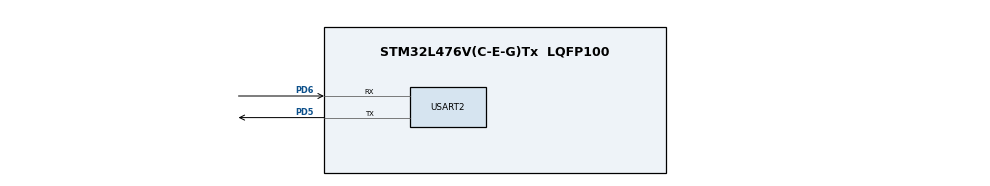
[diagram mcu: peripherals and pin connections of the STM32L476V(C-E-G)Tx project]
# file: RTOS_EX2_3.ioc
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Mcu.Family=STM32L4
Mcu.Name=STM32L476V(C-E-G)Tx
Mcu.Package=LQFP100
NVIC.PriorityGroup=NVIC_PRIORITYGROUP_4
NVIC.TIM7_IRQn=true\:0\:0\:false\:false\:true\:true\:true
NVIC.USART2_IRQn=true\:0\:0\:false\:false\:true\:true\:true
PD5.Mode=Asynchronous
PD5.Signal=USART2_TX
PD6.Mode=Asynchronous
PD6.Signal=USART2_RX
ProjectManager.HeapSize=0x200
ProjectManager.StackSize=0x400
ProjectManager.TargetToolchain=EWARM V8
RCC.AHBFreq_Value=80000000
RCC.APB1Freq_Value=80000000
RCC.APB1TimFreq_Value=80000000
RCC.APB2Freq_Value=80000000
RCC.APB2TimFreq_Value=80000000
RCC.CortexFreq_Value=80000000
RCC.HCLKFreq_Value=80000000
RCC.HSE_VALUE=8000000
RCC.HSI_VALUE=16000000
RCC.LSE_VALUE=32768
RCC.MSI_VALUE=4000000
RCC.PLLN=40
RCC.SYSCLKFreq_VALUE=80000000
RCC.SYSCLKSource=RCC_SYSCLKSOURCE_PLLCLK
RCC.VCOOutputFreq_Value=160000000
USART2.VirtualMode-Asynchronous=VM_ASYNC
VP_TIM7_VS_ClockSourceINT.Mode=Enable_Timer
board=custom

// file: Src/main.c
/* USER CODE BEGIN Header */
/**
  ******************************************************************************
  * @file           : main.c
  * @brief          : Main program body
  ******************************************************************************
  * @attention
  *
  * <h2><center>&copy; Copyright (c) 2019 STMicroelectronics.
  * All rights reserved.</center></h2>
  *
  * This software component is licensed by ST under BSD 3-Clause license,
  * the "License"; You may not use this file except in compliance with the
  * License. You may obtain a copy of the License at:
  *                        opensource.org/licenses/BSD-3-Clause
  *
  ******************************************************************************
  */
/* USER CODE END Header */

#include "main.h"

/* USER CODE BEGIN PD */
#define RX_BUFFER_SIZE    32
#define TIMER_BUFFER_SIZE RX_BUFFER_SIZE
#define QUEUE_SIZE        RX_BUFFER_SIZE
#define RX_ONE_BYTE       1
#define START_CMD_SIZE    6
#define STOP_CMD_SIZE     5

#define START_CMD         "start\n"
#define STOP_CMD          "stop\n"
#define LF                '\n'
#define CR                '\r'
#define CR_LF             "\r\n"
/* USER CODE END PD */

TIM_HandleTypeDef htim7;

UART_HandleTypeDef huart2;

/* USER CODE BEGIN PV */
uint8_t aRxBuffer[RX_BUFFER_SIZE];
uint8_t aTimerBuffer[TIMER_BUFFER_SIZE] = "\r\nTimer Period Elapsed \r\n";
uint8_t uTimerCounter = 0;
uint8_t byte;
volatile uint8_t index;
uint8_t size_of_last_data = 0;
/* USER CODE END PV */

void SystemClock_Config(void);
static void MX_GPIO_Init(void);
static void MX_USART2_UART_Init(void);
static void MX_TIM7_Init(void);
/* USER CODE BEGIN PFP */
static void process_cmd(uint8_t *aRxBuffer, uint8_t current_index);
/* USER CODE END PFP */

int main(void)
{

  /* MCU Configuration--------------------------------------------------------*/

  /* Reset of all peripherals, Initializes the Flash interface and the Systick. */
  HAL_Init();

  /* Configure the system clock */
  SystemClock_Config();

  /* Initialize all configured peripherals */
  MX_GPIO_Init();
  MX_USART2_UART_Init();
  MX_TIM7_Init();
  /* USER CODE BEGIN 2 */
  HAL_UART_Receive_IT(&huart2, &byte, RX_ONE_BYTE);
  /* USER CODE END 2 */

  /* Infinite loop */
  /* USER CODE BEGIN WHILE */
  while (1)
  {
//    printf("Running in main\r\n");
//    HAL_Delay(1000);
    /* USER CODE END WHILE */
  }
}

void SystemClock_Config(void)
{
  RCC_ClkInitTypeDef RCC_ClkInitStruct = {0};
  RCC_OscInitTypeDef RCC_OscInitStruct = {0};

  /* The following clock configuration sets the Clock configuration sets after System reset                */
  /* It could be avoided but it is kept to illustrate the use of HAL_RCC_OscConfig and HAL_RCC_ClockConfig */
  /* and to be eventually adapted to new clock configuration                                               */

  /* MSI is enabled after System reset at 4Mhz, PLL not used */
  RCC_OscInitStruct.OscillatorType = RCC_OSCILLATORTYPE_MSI;
  RCC_OscInitStruct.MSIState = RCC_MSI_ON;
  RCC_OscInitStruct.MSIClockRange = RCC_MSIRANGE_6;
  RCC_OscInitStruct.MSICalibrationValue = RCC_MSICALIBRATION_DEFAULT;
  RCC_OscInitStruct.PLL.PLLState = RCC_PLL_NONE;
  if(HAL_RCC_OscConfig(&RCC_OscInitStruct) != HAL_OK)
  {
    /* Initialization Error */
    while(1);
  }

  /* Select MSI as system clock source and configure the HCLK, PCLK1 and PCLK2 clocks dividers */
  /* Set 0 Wait State flash latency for 4Mhz */
  RCC_ClkInitStruct.ClockType = (RCC_CLOCKTYPE_SYSCLK | RCC_CLOCKTYPE_HCLK | RCC_CLOCKTYPE_PCLK1 | RCC_CLOCKTYPE_PCLK2);
  RCC_ClkInitStruct.SYSCLKSource = RCC_SYSCLKSOURCE_MSI;
  RCC_ClkInitStruct.AHBCLKDivider = RCC_SYSCLK_DIV1;
  RCC_ClkInitStruct.APB1CLKDivider = RCC_HCLK_DIV1;
  RCC_ClkInitStruct.APB2CLKDivider = RCC_HCLK_DIV1;
  if(HAL_RCC_ClockConfig(&RCC_ClkInitStruct, FLASH_LATENCY_0) != HAL_OK)
  {
    /* Initialization Error */
    while(1);
  }
}

/*
  In terms of frequency:
  HandleTimer.Init.Prescaler = Timer'sClockFrequency/DesiredFrequency -1;

  In terms of period:
  HandleTimer.Init.Prescaler = Timer'sClockFrequency*DesiredPeriod -1;

  Frequency is in Hz.
  Period in Seconds.

  Example to get a counter period 1 sec (1HZ)
  HandleTimer.Init.Prescaler = Timer'sClockFrequency -1;

  Example to get a counter frequency 100 Hz (10 msec period)
  HandleTimer.Init.Prescaler = Timer'sClockFrequency/100 -1;
*/
static void MX_TIM7_Init(void)
{
  TIM_MasterConfigTypeDef sMasterConfig = {0};

  htim7.Instance = TIM7;
  htim7.Init.Prescaler = 3999;
  htim7.Init.CounterMode = TIM_COUNTERMODE_UP;
  htim7.Init.Period = 999;
  htim7.Init.AutoReloadPreload = TIM_AUTORELOAD_PRELOAD_DISABLE;
  if (HAL_TIM_Base_Init(&htim7) != HAL_OK)
  {
    Error_Handler();
  }
  sMasterConfig.MasterOutputTrigger = TIM_TRGO_RESET;
  sMasterConfig.MasterSlaveMode = TIM_MASTERSLAVEMODE_DISABLE;
  if (HAL_TIMEx_MasterConfigSynchronization(&htim7, &sMasterConfig) != HAL_OK)
  {
    Error_Handler();
  }
}

static void MX_USART2_UART_Init(void)
{

  huart2.Instance = USART2;
  huart2.Init.BaudRate = 115200;
  huart2.Init.WordLength = UART_WORDLENGTH_8B;
  huart2.Init.StopBits = UART_STOPBITS_1;
  huart2.Init.Parity = UART_PARITY_NONE;
  huart2.Init.Mode = UART_MODE_TX_RX;
  huart2.Init.HwFlowCtl = UART_HWCONTROL_NONE;
  huart2.Init.OverSampling = UART_OVERSAMPLING_16;
  huart2.Init.OneBitSampling = UART_ONE_BIT_SAMPLE_DISABLE;
  huart2.AdvancedInit.AdvFeatureInit = UART_ADVFEATURE_NO_INIT;
  if (HAL_UART_Init(&huart2) != HAL_OK)
  {
    Error_Handler();
  }

}

static void MX_GPIO_Init(void)
{

  /* GPIO Ports Clock Enable */
  __HAL_RCC_GPIOD_CLK_ENABLE();

}

/* USER CODE BEGIN 4 */
void HAL_UART_RxCpltCallback(UART_HandleTypeDef *huart)
{
  // printf("Rx Callback\r\n");
  if (huart->Instance == USART2)
  {
    // TODO: Protect this buffer when writing.
    aRxBuffer[index] = byte;
    // TODO: Move this process to a FreeRTOS Task.
    if (byte == LF)
    {
      // printf("Should Echo Here\n");
      HAL_UART_Transmit(&huart2, aRxBuffer, index, 100);
      if (memcmp(aRxBuffer, START_CMD, START_CMD_SIZE) == 0)
      {
        // Start timer
        HAL_UART_Transmit_IT(&huart2, "\r\nStarting Timer\r\n", 18);
        HAL_TIM_Base_Start_IT(&htim7);
      }
      else if (memcmp(aRxBuffer, STOP_CMD, STOP_CMD_SIZE) == 0)
      {
        // Stop timer
        HAL_UART_Transmit_IT(&huart2, "\r\nStopping Timer\r\n", 18);
        HAL_TIM_Base_Stop_IT(&htim7);
        uTimerCounter = 0;
      }
      memset(aRxBuffer, 0, RX_BUFFER_SIZE);
      index = 0;
    }
    else
    {
      index++;
    }
    HAL_UART_Receive_IT(&huart2, &byte, RX_ONE_BYTE);
  }
}

/**
  * @brief  Period elapsed callback in non blocking mode
  * @note   This function is called  when TIM6 interrupt took place, inside
  * HAL_TIM_IRQHandler(). It makes a direct call to HAL_IncTick() to increment
  * a global variable "uwTick" used as application time base.
  * @param  htim : TIM handle
  * @retval None
  */
void HAL_TIM_PeriodElapsedCallback(TIM_HandleTypeDef *htim)
{
  if (htim->Instance == TIM7)
  {
    // memcpy(aTimerBuffer+22, &uTimerCounter, 3);
    snprintf((char *) aTimerBuffer+23, TIMER_BUFFER_SIZE, "%d", uTimerCounter);
    HAL_UART_Transmit_IT(&huart2, aTimerBuffer, TIMER_BUFFER_SIZE);
    uTimerCounter++;
  }
}

static void process_cmd(uint8_t *aRxBuffer, uint8_t current_index)
{
  uint8_t start_cmd_index;
  uint8_t stop_cmd_index;

  start_cmd_index = current_index - START_CMD_SIZE;
  stop_cmd_index = current_index - STOP_CMD_SIZE;

  if (memcmp(aRxBuffer + start_cmd_index, START_CMD, START_CMD_SIZE) == 0)
  {
    // Start timer
    HAL_UART_Transmit_IT(&huart2, "\r\nStarting Timer\r\n", 18);
  }
  else if (memcmp(aRxBuffer + stop_cmd_index, STOP_CMD, STOP_CMD_SIZE) == 0)
  {
    // Stop timer
    HAL_UART_Transmit_IT(&huart2, "\r\nStopping Timer\r\n", 18);
  }
}
/* USER CODE END 4 */

void Error_Handler(void)
{
  /* USER CODE BEGIN Error_Handler_Debug */
  /* User can add his own implementation to report the HAL error return state */
  printf("Error Handler\r\n");
  while (1);
  /* USER CODE END Error_Handler_Debug */
}

/************************ (C) COPYRIGHT STMicroelectronics *****END OF FILE****/
